! (c) 2009  Infineon Technologies AG, Munich
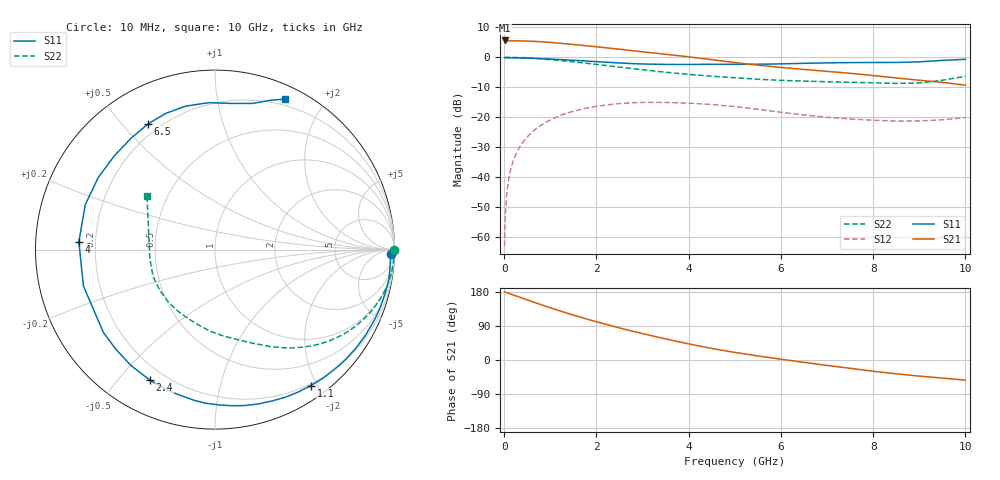
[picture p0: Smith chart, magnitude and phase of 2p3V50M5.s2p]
! Infineon Technologies  Discrete & RF Semiconductors
! BFP420
! VCE =  3.5 V,  IC =  0.5 mA
! Common Emitter S-Parameters:  Nov 2009
# GHz  S  MA  R  50
!  f  S11  S21  S12  S22
! GHz  MAG  ANG  MAG  ANG  MAG  ANG  MAG  ANG
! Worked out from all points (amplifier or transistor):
!   46 points, 10 MHz to 10 GHz, reference 50 ohm
!   highest |S21| = 5.6 dB at 10 MHz (marker M1)
!   |S21| within 3 dB of that: start of sweep to 2.547 GHz
!   unconditionally stable (mu >= 1): 4.466 GHz to end of sweep
!   at 300 MHz: K = 0.02, MSG = 18.2 dB, |S12| = -31.0 dB
!   at 1.7 GHz: K = 0.26, MSG = 10.6 dB, |S12| = -17.2 dB
!   at 10 GHz: K = 1.58, MAG = 0.9 dB, |S12| = -20.1 dB
!   lowest NFmin = 0.68 dB at 900 MHz
!   S11 on the Smith chart (normalised r, x): 10 MHz: 40, -47; 1.1 GHz: 0.18, -1.92; 2.4 GHz: 0.14, -0.61; 4 GHz: 0.14, +0.03; 6.5 GHz: 0.16, +0.59; 10 GHz: 0.13, +1.56
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0.01  0.9793 -1.4  1.913 179.4  0.0007 68.2  0.9991 -0.1
0.02  0.984 -1.2  1.859 179.6  0.0019 83.9  0.9981 -0.5
0.05  0.9788 -2.2  1.872 177.9  0.0047 86.7  0.9987 -1.2
0.1  0.98 -5.0  1.88 175.9  0.0094 86.4  0.9981 -2.6
0.15  0.9809 -7.4  1.885 173.7  0.0142 85.4  0.9969 -3.9
0.25  0.9803 -12.3  1.878 169.3  0.0236 82.4  0.993 -6.5
0.4  0.9757 -19.8  1.874 163.0  0.0376 77.8  0.9836 -10.4
0.6  0.9646 -29.8  1.852 154.3  0.056 71.5  0.9658 -15.4
0.9  0.9429 -44.8  1.796 141.8  0.0819 62.1  0.9294 -22.6
1.1  0.927 -54.8  1.747 133.9  0.0977 56.1  0.9012 -27.1
1.4  0.9008 -69.6  1.666 122.3  0.1192 47.0  0.8554 -33.6
1.7  0.8747 -84.0  1.586 111.4  0.1373 38.4  0.8082 -39.4
2.4  0.8127 -116.6  1.392 87.8  0.1663 19.7  0.7017 -51.3
3  0.7744 -143.4  1.237 69.7  0.1764 5.1  0.6212 -60.4
3.5  0.7607 -164.5  1.124 55.6  0.1763 -5.6  0.5635 -67.9
4  0.7598 176.7  1.018 42.6  0.1715 -14.8  0.5182 -75.7
4.5  0.7649 160.9  0.914 30.4  0.1629 -23.2  0.4841 -84.3
5.5  0.7665 137.1  0.739 10.7  0.1356 -35.6  0.4308 -102.0
6.5  0.7936 118.0  0.627 -6.2  0.1089 -39.7  0.4007 -121.2
7  0.8073 109.7  0.582 -14.3  0.0997 -38.8  0.3907 -131.7
8.5  0.8198 83.3  0.452 -36.4  0.0861 -30.7  0.3663 -172.1
10  0.9253 65.0  0.343 -53.1  0.0984 -19.5  0.4811 142.0
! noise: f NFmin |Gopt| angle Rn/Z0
0.9  0.68  0.78  35  0.65
1.8  1.42  0.6  75  0.5
2.4  1.57  0.58  98  0.37
3  2.1  0.58  128  0.24
4  2.49  0.57  177  0.09
